VERSION 5.7 ;
BUSBITCHARS "[]" ;
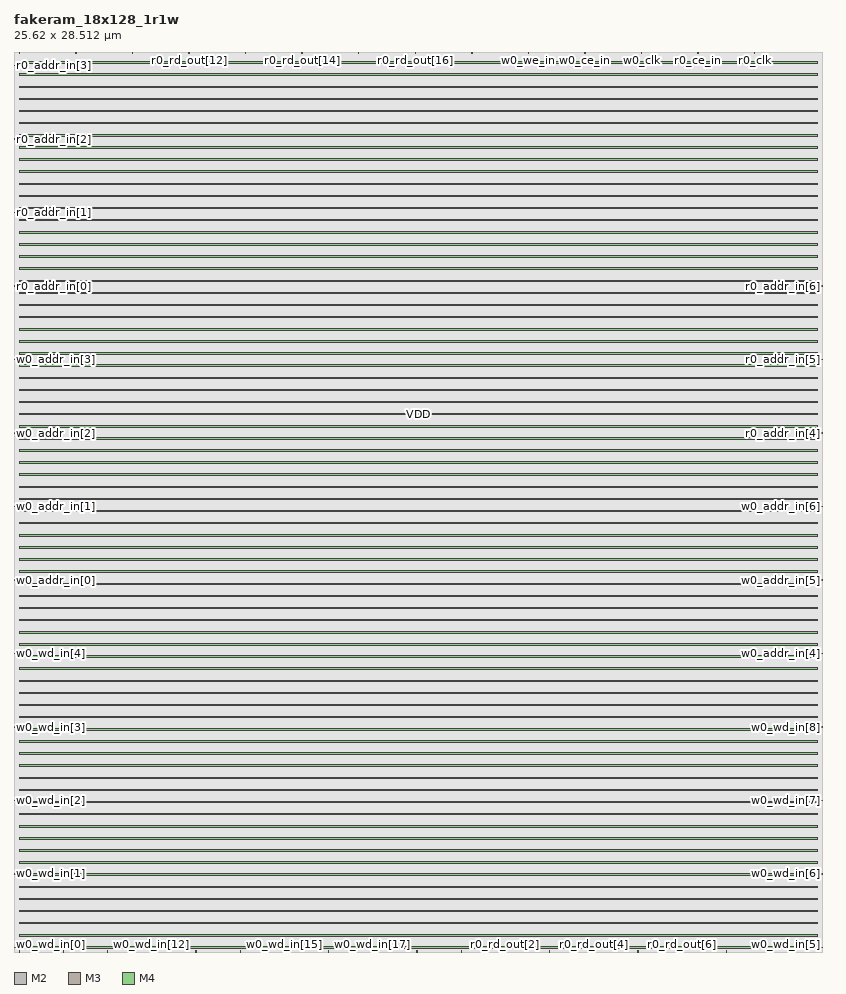
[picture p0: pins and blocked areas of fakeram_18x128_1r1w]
MACRO fakeram_18x128_1r1w
  FOREIGN fakeram_18x128_1r1w 0 0 ;
  SYMMETRY X Y R90 ;
  SIZE 25.620 BY 28.512 ;
  CLASS BLOCK ;
  PIN w0_wd_in[0]
    DIRECTION INPUT ;
    USE SIGNAL ;
    SHAPE ABUTMENT ;
    PORT
      LAYER M2 ;
      RECT 0.000 0.138 0.036 0.150 ;
    END
  END w0_wd_in[0]
  PIN w0_wd_in[1]
    DIRECTION INPUT ;
    USE SIGNAL ;
    SHAPE ABUTMENT ;
    PORT
      LAYER M2 ;
      RECT 0.000 2.466 0.036 2.478 ;
    END
  END w0_wd_in[1]
  PIN w0_wd_in[2]
    DIRECTION INPUT ;
    USE SIGNAL ;
    SHAPE ABUTMENT ;
    PORT
      LAYER M2 ;
      RECT 0.000 4.794 0.036 4.806 ;
    END
  END w0_wd_in[2]
  PIN w0_wd_in[3]
    DIRECTION INPUT ;
    USE SIGNAL ;
    SHAPE ABUTMENT ;
    PORT
      LAYER M2 ;
      RECT 0.000 7.122 0.036 7.134 ;
    END
  END w0_wd_in[3]
  PIN w0_wd_in[4]
    DIRECTION INPUT ;
    USE SIGNAL ;
    SHAPE ABUTMENT ;
    PORT
      LAYER M2 ;
      RECT 0.000 9.450 0.036 9.462 ;
    END
  END w0_wd_in[4]
  PIN w0_wd_in[5]
    DIRECTION INPUT ;
    USE SIGNAL ;
    SHAPE ABUTMENT ;
    PORT
      LAYER M2 ;
      RECT 25.584 0.138 25.620 0.150 ;
    END
  END w0_wd_in[5]
  PIN w0_wd_in[6]
    DIRECTION INPUT ;
    USE SIGNAL ;
    SHAPE ABUTMENT ;
    PORT
      LAYER M2 ;
      RECT 25.584 2.466 25.620 2.478 ;
    END
  END w0_wd_in[6]
  PIN w0_wd_in[7]
    DIRECTION INPUT ;
    USE SIGNAL ;
    SHAPE ABUTMENT ;
    PORT
      LAYER M2 ;
      RECT 25.584 4.794 25.620 4.806 ;
    END
  END w0_wd_in[7]
  PIN w0_wd_in[8]
    DIRECTION INPUT ;
    USE SIGNAL ;
    SHAPE ABUTMENT ;
    PORT
      LAYER M2 ;
      RECT 25.584 7.122 25.620 7.134 ;
    END
  END w0_wd_in[8]
  PIN w0_wd_in[9]
    DIRECTION INPUT ;
    USE SIGNAL ;
    SHAPE ABUTMENT ;
    PORT
      LAYER M3 ;
      RECT 0.161 0.000 0.175 0.042 ;
    END
  END w0_wd_in[9]
  PIN w0_wd_in[10]
    DIRECTION INPUT ;
    USE SIGNAL ;
    SHAPE ABUTMENT ;
    PORT
      LAYER M3 ;
      RECT 1.561 0.000 1.575 0.042 ;
    END
  END w0_wd_in[10]
  PIN w0_wd_in[11]
    DIRECTION INPUT ;
    USE SIGNAL ;
    SHAPE ABUTMENT ;
    PORT
      LAYER M3 ;
      RECT 2.961 0.000 2.975 0.042 ;
    END
  END w0_wd_in[11]
  PIN w0_wd_in[12]
    DIRECTION INPUT ;
    USE SIGNAL ;
    SHAPE ABUTMENT ;
    PORT
      LAYER M3 ;
      RECT 4.361 0.000 4.375 0.042 ;
    END
  END w0_wd_in[12]
  PIN w0_wd_in[13]
    DIRECTION INPUT ;
    USE SIGNAL ;
    SHAPE ABUTMENT ;
    PORT
      LAYER M3 ;
      RECT 5.761 0.000 5.775 0.042 ;
    END
  END w0_wd_in[13]
  PIN w0_wd_in[14]
    DIRECTION INPUT ;
    USE SIGNAL ;
    SHAPE ABUTMENT ;
    PORT
      LAYER M3 ;
      RECT 7.161 0.000 7.175 0.042 ;
    END
  END w0_wd_in[14]
  PIN w0_wd_in[15]
    DIRECTION INPUT ;
    USE SIGNAL ;
    SHAPE ABUTMENT ;
    PORT
      LAYER M3 ;
      RECT 8.561 0.000 8.575 0.042 ;
    END
  END w0_wd_in[15]
  PIN w0_wd_in[16]
    DIRECTION INPUT ;
    USE SIGNAL ;
    SHAPE ABUTMENT ;
    PORT
      LAYER M3 ;
      RECT 9.961 0.000 9.975 0.042 ;
    END
  END w0_wd_in[16]
  PIN w0_wd_in[17]
    DIRECTION INPUT ;
    USE SIGNAL ;
    SHAPE ABUTMENT ;
    PORT
      LAYER M3 ;
      RECT 11.361 0.000 11.375 0.042 ;
    END
  END w0_wd_in[17]
  PIN r0_rd_out[0]
    DIRECTION OUTPUT ;
    USE SIGNAL ;
    SHAPE ABUTMENT ;
    PORT
      LAYER M3 ;
      RECT 12.761 0.000 12.775 0.042 ;
    END
  END r0_rd_out[0]
  PIN r0_rd_out[1]
    DIRECTION OUTPUT ;
    USE SIGNAL ;
    SHAPE ABUTMENT ;
    PORT
      LAYER M3 ;
      RECT 14.161 0.000 14.175 0.042 ;
    END
  END r0_rd_out[1]
  PIN r0_rd_out[2]
    DIRECTION OUTPUT ;
    USE SIGNAL ;
    SHAPE ABUTMENT ;
    PORT
      LAYER M3 ;
      RECT 15.561 0.000 15.575 0.042 ;
    END
  END r0_rd_out[2]
  PIN r0_rd_out[3]
    DIRECTION OUTPUT ;
    USE SIGNAL ;
    SHAPE ABUTMENT ;
    PORT
      LAYER M3 ;
      RECT 16.961 0.000 16.975 0.042 ;
    END
  END r0_rd_out[3]
  PIN r0_rd_out[4]
    DIRECTION OUTPUT ;
    USE SIGNAL ;
    SHAPE ABUTMENT ;
    PORT
      LAYER M3 ;
      RECT 18.361 0.000 18.375 0.042 ;
    END
  END r0_rd_out[4]
  PIN r0_rd_out[5]
    DIRECTION OUTPUT ;
    USE SIGNAL ;
    SHAPE ABUTMENT ;
    PORT
      LAYER M3 ;
      RECT 19.761 0.000 19.775 0.042 ;
    END
  END r0_rd_out[5]
  PIN r0_rd_out[6]
    DIRECTION OUTPUT ;
    USE SIGNAL ;
    SHAPE ABUTMENT ;
    PORT
      LAYER M3 ;
      RECT 21.161 0.000 21.175 0.042 ;
    END
  END r0_rd_out[6]
  PIN r0_rd_out[7]
    DIRECTION OUTPUT ;
    USE SIGNAL ;
    SHAPE ABUTMENT ;
    PORT
      LAYER M3 ;
      RECT 22.561 0.000 22.575 0.042 ;
    END
  END r0_rd_out[7]
  PIN r0_rd_out[8]
    DIRECTION OUTPUT ;
    USE SIGNAL ;
    SHAPE ABUTMENT ;
    PORT
      LAYER M3 ;
      RECT 23.961 0.000 23.975 0.042 ;
    END
  END r0_rd_out[8]
  PIN r0_rd_out[9]
    DIRECTION OUTPUT ;
    USE SIGNAL ;
    SHAPE ABUTMENT ;
    PORT
      LAYER M3 ;
      RECT 0.161 28.470 0.175 28.512 ;
    END
  END r0_rd_out[9]
  PIN r0_rd_out[10]
    DIRECTION OUTPUT ;
    USE SIGNAL ;
    SHAPE ABUTMENT ;
    PORT
      LAYER M3 ;
      RECT 1.953 28.470 1.967 28.512 ;
    END
  END r0_rd_out[10]
  PIN r0_rd_out[11]
    DIRECTION OUTPUT ;
    USE SIGNAL ;
    SHAPE ABUTMENT ;
    PORT
      LAYER M3 ;
      RECT 3.745 28.470 3.759 28.512 ;
    END
  END r0_rd_out[11]
  PIN r0_rd_out[12]
    DIRECTION OUTPUT ;
    USE SIGNAL ;
    SHAPE ABUTMENT ;
    PORT
      LAYER M3 ;
      RECT 5.537 28.470 5.551 28.512 ;
    END
  END r0_rd_out[12]
  PIN r0_rd_out[13]
    DIRECTION OUTPUT ;
    USE SIGNAL ;
    SHAPE ABUTMENT ;
    PORT
      LAYER M3 ;
      RECT 7.329 28.470 7.343 28.512 ;
    END
  END r0_rd_out[13]
  PIN r0_rd_out[14]
    DIRECTION OUTPUT ;
    USE SIGNAL ;
    SHAPE ABUTMENT ;
    PORT
      LAYER M3 ;
      RECT 9.121 28.470 9.135 28.512 ;
    END
  END r0_rd_out[14]
  PIN r0_rd_out[15]
    DIRECTION OUTPUT ;
    USE SIGNAL ;
    SHAPE ABUTMENT ;
    PORT
      LAYER M3 ;
      RECT 10.913 28.470 10.927 28.512 ;
    END
  END r0_rd_out[15]
  PIN r0_rd_out[16]
    DIRECTION OUTPUT ;
    USE SIGNAL ;
    SHAPE ABUTMENT ;
    PORT
      LAYER M3 ;
      RECT 12.705 28.470 12.719 28.512 ;
    END
  END r0_rd_out[16]
  PIN r0_rd_out[17]
    DIRECTION OUTPUT ;
    USE SIGNAL ;
    SHAPE ABUTMENT ;
    PORT
      LAYER M3 ;
      RECT 14.497 28.470 14.511 28.512 ;
    END
  END r0_rd_out[17]
  PIN w0_addr_in[0]
    DIRECTION INPUT ;
    USE SIGNAL ;
    SHAPE ABUTMENT ;
    PORT
      LAYER M2 ;
      RECT 0.000 11.778 0.036 11.790 ;
    END
  END w0_addr_in[0]
  PIN w0_addr_in[1]
    DIRECTION INPUT ;
    USE SIGNAL ;
    SHAPE ABUTMENT ;
    PORT
      LAYER M2 ;
      RECT 0.000 14.106 0.036 14.118 ;
    END
  END w0_addr_in[1]
  PIN w0_addr_in[2]
    DIRECTION INPUT ;
    USE SIGNAL ;
    SHAPE ABUTMENT ;
    PORT
      LAYER M2 ;
      RECT 0.000 16.434 0.036 16.446 ;
    END
  END w0_addr_in[2]
  PIN w0_addr_in[3]
    DIRECTION INPUT ;
    USE SIGNAL ;
    SHAPE ABUTMENT ;
    PORT
      LAYER M2 ;
      RECT 0.000 18.762 0.036 18.774 ;
    END
  END w0_addr_in[3]
  PIN w0_addr_in[4]
    DIRECTION INPUT ;
    USE SIGNAL ;
    SHAPE ABUTMENT ;
    PORT
      LAYER M2 ;
      RECT 25.584 9.450 25.620 9.462 ;
    END
  END w0_addr_in[4]
  PIN w0_addr_in[5]
    DIRECTION INPUT ;
    USE SIGNAL ;
    SHAPE ABUTMENT ;
    PORT
      LAYER M2 ;
      RECT 25.584 11.778 25.620 11.790 ;
    END
  END w0_addr_in[5]
  PIN w0_addr_in[6]
    DIRECTION INPUT ;
    USE SIGNAL ;
    SHAPE ABUTMENT ;
    PORT
      LAYER M2 ;
      RECT 25.584 14.106 25.620 14.118 ;
    END
  END w0_addr_in[6]
  PIN r0_addr_in[0]
    DIRECTION INPUT ;
    USE SIGNAL ;
    SHAPE ABUTMENT ;
    PORT
      LAYER M2 ;
      RECT 0.000 21.090 0.036 21.102 ;
    END
  END r0_addr_in[0]
  PIN r0_addr_in[1]
    DIRECTION INPUT ;
    USE SIGNAL ;
    SHAPE ABUTMENT ;
    PORT
      LAYER M2 ;
      RECT 0.000 23.418 0.036 23.430 ;
    END
  END r0_addr_in[1]
  PIN r0_addr_in[2]
    DIRECTION INPUT ;
    USE SIGNAL ;
    SHAPE ABUTMENT ;
    PORT
      LAYER M2 ;
      RECT 0.000 25.746 0.036 25.758 ;
    END
  END r0_addr_in[2]
  PIN r0_addr_in[3]
    DIRECTION INPUT ;
    USE SIGNAL ;
    SHAPE ABUTMENT ;
    PORT
      LAYER M2 ;
      RECT 0.000 28.074 0.036 28.086 ;
    END
  END r0_addr_in[3]
  PIN r0_addr_in[4]
    DIRECTION INPUT ;
    USE SIGNAL ;
    SHAPE ABUTMENT ;
    PORT
      LAYER M2 ;
      RECT 25.584 16.434 25.620 16.446 ;
    END
  END r0_addr_in[4]
  PIN r0_addr_in[5]
    DIRECTION INPUT ;
    USE SIGNAL ;
    SHAPE ABUTMENT ;
    PORT
      LAYER M2 ;
      RECT 25.584 18.762 25.620 18.774 ;
    END
  END r0_addr_in[5]
  PIN r0_addr_in[6]
    DIRECTION INPUT ;
    USE SIGNAL ;
    SHAPE ABUTMENT ;
    PORT
      LAYER M2 ;
      RECT 25.584 21.090 25.620 21.102 ;
    END
  END r0_addr_in[6]
  PIN w0_we_in
    DIRECTION INPUT ;
    USE SIGNAL ;
    SHAPE ABUTMENT ;
    PORT
      LAYER M3 ;
      RECT 16.289 28.470 16.303 28.512 ;
    END
  END w0_we_in
  PIN w0_ce_in
    DIRECTION INPUT ;
    USE SIGNAL ;
    SHAPE ABUTMENT ;
    PORT
      LAYER M3 ;
      RECT 18.081 28.470 18.095 28.512 ;
    END
  END w0_ce_in
  PIN w0_clk
    DIRECTION INPUT ;
    USE SIGNAL ;
    SHAPE ABUTMENT ;
    PORT
      LAYER M3 ;
      RECT 19.873 28.470 19.887 28.512 ;
    END
  END w0_clk
  PIN r0_ce_in
    DIRECTION INPUT ;
    USE SIGNAL ;
    SHAPE ABUTMENT ;
    PORT
      LAYER M3 ;
      RECT 21.665 28.470 21.679 28.512 ;
    END
  END r0_ce_in
  PIN r0_clk
    DIRECTION INPUT ;
    USE SIGNAL ;
    SHAPE ABUTMENT ;
    PORT
      LAYER M3 ;
      RECT 23.457 28.470 23.471 28.512 ;
    END
  END r0_clk
  PIN VSS
    DIRECTION INOUT ;
    USE GROUND ;
    PORT
      LAYER M4 ;
      RECT 0.168 0.120 25.452 0.168 ;
      RECT 0.168 0.504 25.452 0.552 ;
      RECT 0.168 0.888 25.452 0.936 ;
      RECT 0.168 1.272 25.452 1.320 ;
      RECT 0.168 1.656 25.452 1.704 ;
      RECT 0.168 2.040 25.452 2.088 ;
      RECT 0.168 2.424 25.452 2.472 ;
      RECT 0.168 2.808 25.452 2.856 ;
      RECT 0.168 3.192 25.452 3.240 ;
      RECT 0.168 3.576 25.452 3.624 ;
      RECT 0.168 3.960 25.452 4.008 ;
      RECT 0.168 4.344 25.452 4.392 ;
      RECT 0.168 4.728 25.452 4.776 ;
      RECT 0.168 5.112 25.452 5.160 ;
      RECT 0.168 5.496 25.452 5.544 ;
      RECT 0.168 5.880 25.452 5.928 ;
      RECT 0.168 6.264 25.452 6.312 ;
      RECT 0.168 6.648 25.452 6.696 ;
      RECT 0.168 7.032 25.452 7.080 ;
      RECT 0.168 7.416 25.452 7.464 ;
      RECT 0.168 7.800 25.452 7.848 ;
      RECT 0.168 8.184 25.452 8.232 ;
      RECT 0.168 8.568 25.452 8.616 ;
      RECT 0.168 8.952 25.452 9.000 ;
      RECT 0.168 9.336 25.452 9.384 ;
      RECT 0.168 9.720 25.452 9.768 ;
      RECT 0.168 10.104 25.452 10.152 ;
      RECT 0.168 10.488 25.452 10.536 ;
      RECT 0.168 10.872 25.452 10.920 ;
      RECT 0.168 11.256 25.452 11.304 ;
      RECT 0.168 11.640 25.452 11.688 ;
      RECT 0.168 12.024 25.452 12.072 ;
      RECT 0.168 12.408 25.452 12.456 ;
      RECT 0.168 12.792 25.452 12.840 ;
      RECT 0.168 13.176 25.452 13.224 ;
      RECT 0.168 13.560 25.452 13.608 ;
      RECT 0.168 13.944 25.452 13.992 ;
      RECT 0.168 14.328 25.452 14.376 ;
      RECT 0.168 14.712 25.452 14.760 ;
      RECT 0.168 15.096 25.452 15.144 ;
      RECT 0.168 15.480 25.452 15.528 ;
      RECT 0.168 15.864 25.452 15.912 ;
      RECT 0.168 16.248 25.452 16.296 ;
      RECT 0.168 16.632 25.452 16.680 ;
      RECT 0.168 17.016 25.452 17.064 ;
      RECT 0.168 17.400 25.452 17.448 ;
      RECT 0.168 17.784 25.452 17.832 ;
      RECT 0.168 18.168 25.452 18.216 ;
      RECT 0.168 18.552 25.452 18.600 ;
      RECT 0.168 18.936 25.452 18.984 ;
      RECT 0.168 19.320 25.452 19.368 ;
      RECT 0.168 19.704 25.452 19.752 ;
      RECT 0.168 20.088 25.452 20.136 ;
      RECT 0.168 20.472 25.452 20.520 ;
      RECT 0.168 20.856 25.452 20.904 ;
      RECT 0.168 21.240 25.452 21.288 ;
      RECT 0.168 21.624 25.452 21.672 ;
      RECT 0.168 22.008 25.452 22.056 ;
      RECT 0.168 22.392 25.452 22.440 ;
      RECT 0.168 22.776 25.452 22.824 ;
      RECT 0.168 23.160 25.452 23.208 ;
      RECT 0.168 23.544 25.452 23.592 ;
      RECT 0.168 23.928 25.452 23.976 ;
      RECT 0.168 24.312 25.452 24.360 ;
      RECT 0.168 24.696 25.452 24.744 ;
      RECT 0.168 25.080 25.452 25.128 ;
      RECT 0.168 25.464 25.452 25.512 ;
      RECT 0.168 25.848 25.452 25.896 ;
      RECT 0.168 26.232 25.452 26.280 ;
      RECT 0.168 26.616 25.452 26.664 ;
      RECT 0.168 27.000 25.452 27.048 ;
      RECT 0.168 27.384 25.452 27.432 ;
      RECT 0.168 27.768 25.452 27.816 ;
      RECT 0.168 28.152 25.452 28.200 ;
    END
  END VSS
  PIN VDD
    DIRECTION INOUT ;
    USE POWER ;
    PORT
      LAYER M4 ;
      RECT 0.168 0.120 25.452 0.168 ;
      RECT 0.168 0.504 25.452 0.552 ;
      RECT 0.168 0.888 25.452 0.936 ;
      RECT 0.168 1.272 25.452 1.320 ;
      RECT 0.168 1.656 25.452 1.704 ;
      RECT 0.168 2.040 25.452 2.088 ;
      RECT 0.168 2.424 25.452 2.472 ;
      RECT 0.168 2.808 25.452 2.856 ;
      RECT 0.168 3.192 25.452 3.240 ;
      RECT 0.168 3.576 25.452 3.624 ;
      RECT 0.168 3.960 25.452 4.008 ;
      RECT 0.168 4.344 25.452 4.392 ;
      RECT 0.168 4.728 25.452 4.776 ;
      RECT 0.168 5.112 25.452 5.160 ;
      RECT 0.168 5.496 25.452 5.544 ;
      RECT 0.168 5.880 25.452 5.928 ;
      RECT 0.168 6.264 25.452 6.312 ;
      RECT 0.168 6.648 25.452 6.696 ;
      RECT 0.168 7.032 25.452 7.080 ;
      RECT 0.168 7.416 25.452 7.464 ;
      RECT 0.168 7.800 25.452 7.848 ;
      RECT 0.168 8.184 25.452 8.232 ;
      RECT 0.168 8.568 25.452 8.616 ;
      RECT 0.168 8.952 25.452 9.000 ;
      RECT 0.168 9.336 25.452 9.384 ;
      RECT 0.168 9.720 25.452 9.768 ;
      RECT 0.168 10.104 25.452 10.152 ;
      RECT 0.168 10.488 25.452 10.536 ;
      RECT 0.168 10.872 25.452 10.920 ;
      RECT 0.168 11.256 25.452 11.304 ;
      RECT 0.168 11.640 25.452 11.688 ;
      RECT 0.168 12.024 25.452 12.072 ;
      RECT 0.168 12.408 25.452 12.456 ;
      RECT 0.168 12.792 25.452 12.840 ;
      RECT 0.168 13.176 25.452 13.224 ;
      RECT 0.168 13.560 25.452 13.608 ;
      RECT 0.168 13.944 25.452 13.992 ;
      RECT 0.168 14.328 25.452 14.376 ;
      RECT 0.168 14.712 25.452 14.760 ;
      RECT 0.168 15.096 25.452 15.144 ;
      RECT 0.168 15.480 25.452 15.528 ;
      RECT 0.168 15.864 25.452 15.912 ;
      RECT 0.168 16.248 25.452 16.296 ;
      RECT 0.168 16.632 25.452 16.680 ;
      RECT 0.168 17.016 25.452 17.064 ;
      RECT 0.168 17.400 25.452 17.448 ;
      RECT 0.168 17.784 25.452 17.832 ;
      RECT 0.168 18.168 25.452 18.216 ;
      RECT 0.168 18.552 25.452 18.600 ;
      RECT 0.168 18.936 25.452 18.984 ;
      RECT 0.168 19.320 25.452 19.368 ;
      RECT 0.168 19.704 25.452 19.752 ;
      RECT 0.168 20.088 25.452 20.136 ;
      RECT 0.168 20.472 25.452 20.520 ;
      RECT 0.168 20.856 25.452 20.904 ;
      RECT 0.168 21.240 25.452 21.288 ;
      RECT 0.168 21.624 25.452 21.672 ;
      RECT 0.168 22.008 25.452 22.056 ;
      RECT 0.168 22.392 25.452 22.440 ;
      RECT 0.168 22.776 25.452 22.824 ;
      RECT 0.168 23.160 25.452 23.208 ;
      RECT 0.168 23.544 25.452 23.592 ;
      RECT 0.168 23.928 25.452 23.976 ;
      RECT 0.168 24.312 25.452 24.360 ;
      RECT 0.168 24.696 25.452 24.744 ;
      RECT 0.168 25.080 25.452 25.128 ;
      RECT 0.168 25.464 25.452 25.512 ;
      RECT 0.168 25.848 25.452 25.896 ;
      RECT 0.168 26.232 25.452 26.280 ;
      RECT 0.168 26.616 25.452 26.664 ;
      RECT 0.168 27.000 25.452 27.048 ;
      RECT 0.168 27.384 25.452 27.432 ;
      RECT 0.168 27.768 25.452 27.816 ;
      RECT 0.168 28.152 25.452 28.200 ;
    END
  END VDD
  OBS
    LAYER M1 ;
    RECT 0 0 25.620 28.512 ;
    LAYER M2 ;
    RECT 0 0 25.620 28.512 ;
    LAYER M3 ;
    RECT 0 0 25.620 28.512 ;
    LAYER M4 ;
    RECT 0 0 25.620 28.512 ;
  END
END fakeram_18x128_1r1w

END LIBRARY
